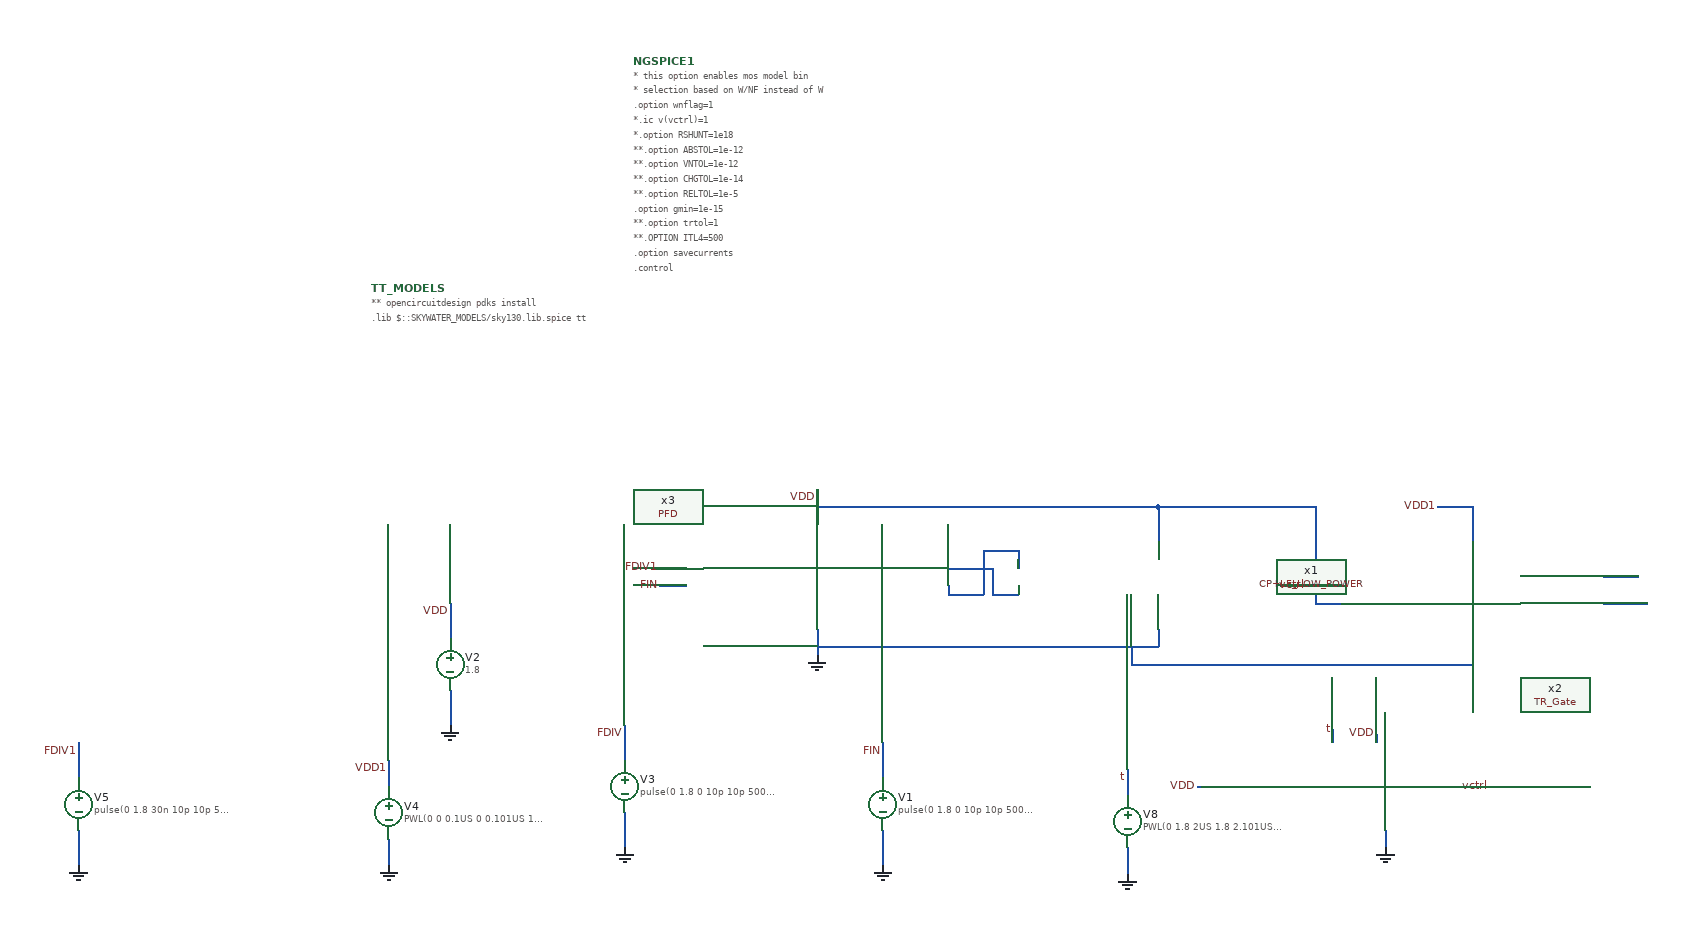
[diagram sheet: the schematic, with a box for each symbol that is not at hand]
v {xschem version=3.4.5 file_version=1.2
}
G {}
K {}
V {}
S {}
E {}
B 2 590 -370 1030 -200 {flags=graph
y1=1.13956
y2=3.04066
ypos1=0
ypos2=2
divy=5
subdivy=1
unity=1
x1=0
x2=1e-05
divx=5
subdivx=1
xlabmag=1.0
ylabmag=1.0
node=net2
color=4
dataset=-1
unitx=1
logx=0
logy=0
}
B 2 590 -180 1030 10 {flags=graph
y1=-0.013
y2=1.9
ypos1=0
ypos2=2
divy=5
subdivy=1
unity=1
x1=0
x2=1e-05
divx=5
subdivx=1
xlabmag=1.0
ylabmag=1.0
node=net1
color=4
dataset=-1
unitx=1
logx=0
logy=0
}
B 2 1060 -210 1490 -20 {flags=graph
y1=-0.16
y2=1.2
ypos1=0
ypos2=2
divy=5
subdivy=1
unity=1
x1=0
x2=1e-05
divx=5
subdivx=1
xlabmag=1.0
ylabmag=1.0
node=x1.dn1
color=4
dataset=-1
unitx=1
logx=0
logy=0
}
B 2 1060 -410 1480 -220 {flags=graph
y1=0
y2=1.8
ypos1=0
ypos2=2
divy=5
subdivy=1
unity=1
x1=0
x2=1e-05
divx=5
subdivx=1
xlabmag=1.0
ylabmag=1.0
node=x1.dnb
color=4
dataset=-1
unitx=1
logx=0
logy=0
}
B 2 590 20 1030 210 {flags=graph
y1=-0.0042
y2=1.9
ypos1=0
ypos2=2
divy=5
subdivy=1
unity=1
x1=0
x2=1e-05
divx=5
subdivx=1
xlabmag=1.0
ylabmag=1.0
node=vctrl
color=4
dataset=-1
unitx=1
logx=0
logy=0
}
B 2 1050 20 1490 210 {flags=graph
y1=-0.0025
y2=1.9
ypos1=0
ypos2=2
divy=5
subdivy=1
unity=1
x1=0
x2=1e-05
divx=5
subdivx=1
xlabmag=1.0
ylabmag=1.0


dataset=-1
unitx=1
logx=0
logy=0

color=4
node=x1.dnb}
B 2 1040 240 1480 430 {flags=graph
y1=-0.24
y2=1.9
ypos1=0
ypos2=2
divy=5
subdivy=1
unity=1
x1=0
x2=1e-05
divx=5
subdivx=1
xlabmag=1.0
ylabmag=1.0


dataset=-1
unitx=1
logx=0
logy=0
color=4
node=x1.dn1}
B 2 590 230 1030 420 {flags=graph
y1=0.38
y2=2.2
ypos1=0
ypos2=2
divy=5
subdivy=1
unity=1
x1=0
x2=1e-05
divx=5
subdivx=1
xlabmag=1.0
ylabmag=1.0
node=x1.cp
color=4
dataset=-1
unitx=1
logx=0
logy=0
}
B 2 590 440 1030 630 {flags=graph
y1=-0.00186
y2=0.00434
ypos1=0
ypos2=2
divy=5
subdivy=1
unity=1
x1=0
x2=1e-05
divx=5
subdivx=1
xlabmag=1.0
ylabmag=1.0
node=i(v1)
color=4
dataset=-1
unitx=1
logx=0
logy=0
}
N -810 40 -810 80 {
lab=VDD}
N -810 140 -810 180 {
lab=GND}
N -315 200 -315 240 {
lab=FIN}
N -315 300 -315 340 {
lab=GND}
N -610 180 -610 220 {
lab=FDIV}
N -610 280 -610 320 {
lab=GND}
N -390 -90 -390 -50 {
lab=VDD}
N -390 70 -390 100 {
lab=GND}
N -580 0 -540 0 {
lab=FDIV1}
N -570 20 -540 20 {
lab=FIN}
N 0 -70 -0 -30 {
lab=VDD}
N -390 -70 -0 -70 {
lab=VDD}
N 0 70 -0 90 {
lab=GND}
N -390 90 -0 90 {
lab=GND}
N 140 20 190 20 {
lab=vctrl}
N 190 20 210 20 {
lab=vctrl}
N 360 90 360 110 {
lab=GND}
N -30 110 360 110 {
lab=GND}
N -30 90 -30 110 {
lab=GND}
N 180 40 210 40 {
lab=VDD}
N 180 -70 180 40 {
lab=VDD}
N -0 -70 180 -70 {
lab=VDD}
N -880 220 -880 250 {
lab=VDD1}
N -880 310 -880 340 {
lab=GND}
N -160 20 -160 30 {
lab=#net1}
N 360 -70 360 -30 {
lab=VDD1}
N 320 -70 360 -70 {
lab=VDD1}
N -1235 200 -1235 240 {
lab=FDIV1}
N -1235 300 -1235 340 {
lab=GND}
N -240 25 -240 30 {
lab=#net2}
N -240 20 -240 25 {
lab=#net2}
N 45 250 50 250 {
lab=VDD}
N 200 185 200 200 {
lab=t}
N 250 190 250 200 {
lab=VDD}
N 260 300 260 320 {
lab=GND}
N 350 250 380 250 {
lab=vctrl}
N -35 230 -35 260 {
lab=t}
N -35 320 -35 350 {
lab=GND}
N -240 -0 -190 0 {
lab=#net1}
N -190 0 -190 30 {
lab=#net1}
N -190 30 -160 30 {
lab=#net1}
N -240 30 -200 30 {
lab=#net2}
N -200 -20 -200 30 {
lab=#net2}
N -200 -20 -160 -20 {
lab=#net2}
N -160 -20 -160 -0 {
lab=#net2}
N 510 10 550 10 {
lab=#net3}
N 510 40 560 40 {
lab=#net4}
C {PFD.sym} -390 10 0 0 {name=x3}
C {devices/code.sym} -900 -320 0 0 {name=TT_MODELS
only_toplevel=true
format="tcleval( @value )"
value="
** opencircuitdesign pdks install
.lib $::SKYWATER_MODELS/sky130.lib.spice tt

"
spice_ignore=false}
C {devices/launcher.sym} -920 -40 0 0 {name=h16 
descr="Load custom waves" 
tclcommand="
xschem raw_read $netlist_dir/filename.raw tran

"
}
C {devices/launcher.sym} -920 -80 0 0 {name=h17 
descr="Load waves" 
tclcommand="
xschem raw_read $netlist_dir/[file tail [file rootname [xschem get current_name]]].raw tran

"
}
C {devices/lab_wire.sym} -810 50 0 0 {name=p58 sig_type=std_logic lab=VDD}
C {devices/lab_wire.sym} -315 210 0 0 {name=p63 sig_type=std_logic lab=FIN}
C {devices/lab_wire.sym} -610 190 0 0 {name=p3 sig_type=std_logic lab=FDIV}
C {devices/lab_pin.sym} -390 -80 0 0 {name=p1 sig_type=std_logic lab=VDD
}
C {devices/lab_wire.sym} -570 20 0 0 {name=p7 sig_type=std_logic lab=FIN}
C {devices/lab_wire.sym} -570 0 0 0 {name=p8 sig_type=std_logic lab=FDIV1}
C {devices/code_shown.sym} -600 -580 0 0 {name=NGSPICE1
only_toplevel=true
value="* this option enables mos model bin 
* selection based on W/NF instead of W
.option wnflag=1 

*.ic v(vctrl)=1
*.option RSHUNT=1e18
**.option ABSTOL=1e-12
**.option VNTOL=1e-12
**.option CHGTOL=1e-14
**.option RELTOL=1e-5
.option gmin=1e-15
**.option trtol=1
**.OPTION ITL4=500
.option savecurrents
.control
save all

*dc v3 0 1.8 0.025 
*plot v(IN) v(OUT)

tran 1000p 10u


write "PFD_LP_CP.raw"
.endc
" }
C {devices/vsource.sym} -810 110 0 0 {name=V2 value=1.8 savecurrent=false}
C {devices/gnd.sym} -810 180 0 0 {name=l1 lab=GND}
C {devices/gnd.sym} -315 340 0 0 {name=l2 lab=GND}
C {devices/gnd.sym} -390 100 0 0 {name=l3 lab=GND}
C {devices/gnd.sym} -610 320 0 0 {name=l4 lab=GND}
C {devices/vsource.sym} -315 270 0 0 {name=V1 value="pulse(0 1.8 0 10p 10p 500n 1000n)"
 savecurrent=false}
C {devices/vsource.sym} -610 250 0 0 {name=V3 value="pulse(0 1.8 0 10p 10p 500n 1000n)"
 savecurrent=false}
C {devices/vsource.sym} -880 280 0 0 {name=V4 value="PWL(0 0 0.1US 0 0.101US 1.8)"}
C {devices/lab_wire.sym} -880 230 0 0 {name=p4 sig_type=std_logic lab=VDD1}
C {devices/gnd.sym} -880 340 0 0 {name=l5 lab=GND}
C {devices/lab_pin.sym} 320 -70 0 0 {name=p2 sig_type=std_logic lab=VDD1
}
C {CP+LF_LOW_POWER.sym} -10 20 0 0 {name=x1}
C {devices/lab_pin.sym} 170 20 1 0 {name=p9 sig_type=std_logic lab=vctrl
}
C {devices/lab_wire.sym} -1235 210 0 0 {name=p10 sig_type=std_logic lab=FDIV1}
C {devices/vsource.sym} -1235 270 0 0 {name=V5 value="pulse(0 1.8 30n 10p 10p 500n 1000n)"
 savecurrent=false
lab=FDIV1}
C {devices/gnd.sym} -1235 340 0 0 {name=l6 lab=GND}
C {devices/gnd.sym} 260 320 0 0 {name=l9 lab=GND}
C {devices/lab_wire.sym} 200 185 0 0 {name=p19 sig_type=std_logic lab=t}
C {devices/lab_pin.sym} 250 190 1 0 {name=p20 sig_type=std_logic lab=VDD
}
C {devices/lab_pin.sym} 380 250 1 0 {name=p21 sig_type=std_logic lab=vctrl
}
C {devices/vsource.sym} -35 290 0 0 {name=V8 value="PWL(0 1.8 2US 1.8 2.101US 0)"}
C {devices/lab_wire.sym} -35 240 0 0 {name=p17 sig_type=std_logic lab=t}
C {devices/gnd.sym} -35 350 0 0 {name=l11 lab=GND}
C {devices/lab_pin.sym} 45 250 1 0 {name=p22 sig_type=std_logic lab=VDD
}
C {TR_Gate.sym} 200 250 0 0 {name=x2}
